One B-rep face of a CAD part: STEP entity #253.
In plain terms, the planar face has unit normal (1, 0, 0).
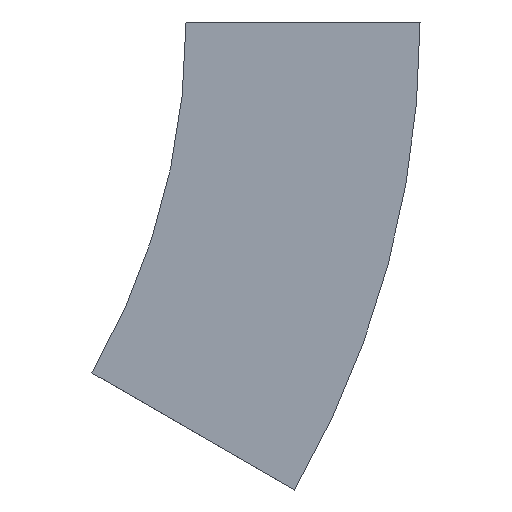
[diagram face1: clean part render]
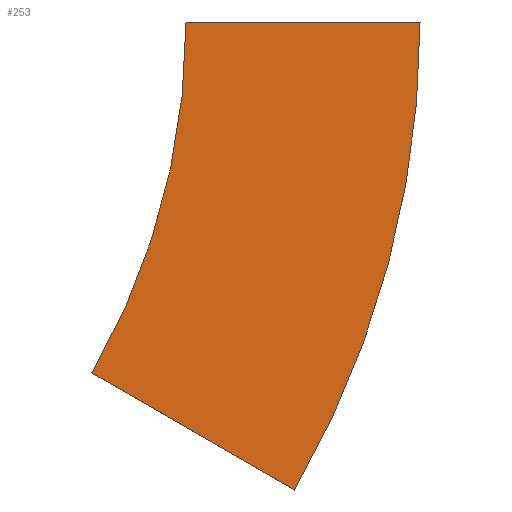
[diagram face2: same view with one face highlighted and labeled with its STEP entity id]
Its self-contained STEP definition (entity closure, numbers rounded to 3 decimals):
#20 = VERTEX_POINT ( 'NONE', #156 ) ;
#25 = VECTOR ( 'NONE', #99, 1000. ) ;
#33 = AXIS2_PLACEMENT_3D ( 'NONE', #85, #275, #437 ) ;
#43 = CIRCLE ( 'NONE', #382, 300. ) ;
#71 = CARTESIAN_POINT ( 'NONE',  ( 0., -46.41, -200. ) ) ;
#72 = ORIENTED_EDGE ( 'NONE', *, *, #209, .F. ) ;
#85 = CARTESIAN_POINT ( 'NONE',  ( 0., -100., 0. ) ) ;
#92 = DIRECTION ( 'NONE',  ( 0., -1., 0. ) ) ;
#99 = DIRECTION ( 'NONE',  ( 0., 1., 0. ) ) ;
#125 = CARTESIAN_POINT ( 'NONE',  ( 0., 0., 0. ) ) ;
#129 = FACE_OUTER_BOUND ( 'NONE', #481, .T. ) ;
#144 = CIRCLE ( 'NONE', #394, 400. ) ;
#146 = VERTEX_POINT ( 'NONE', #125 ) ;
#156 = CARTESIAN_POINT ( 'NONE',  ( 0., 40.192, -150. ) ) ;
#175 = LINE ( 'NONE', #306, #251 ) ;
#180 = CARTESIAN_POINT ( 'NONE',  ( 0., -100., 0. ) ) ;
#209 = EDGE_CURVE ( 'NONE', #483, #146, #294, .T. ) ;
#251 = VECTOR ( 'NONE', #469, 1000. ) ;
#253 = ADVANCED_FACE ( 'NONE', ( #129 ), #473, .F. ) ;
#275 = DIRECTION ( 'NONE',  ( -1., 0., 0. ) ) ;
#278 = CARTESIAN_POINT ( 'NONE',  ( 0., 300., 0. ) ) ;
#281 = ORIENTED_EDGE ( 'NONE', *, *, #511, .T. ) ;
#294 = LINE ( 'NONE', #180, #25 ) ;
#306 = CARTESIAN_POINT ( 'NONE',  ( 0., -46.41, -200. ) ) ;
#316 = CARTESIAN_POINT ( 'NONE',  ( 0., 300., 0. ) ) ;
#328 = VERTEX_POINT ( 'NONE', #71 ) ;
#348 = EDGE_CURVE ( 'NONE', #328, #20, #175, .T. ) ;
#365 = DIRECTION ( 'NONE',  ( 1., 0., 0. ) ) ;
#382 = AXIS2_PLACEMENT_3D ( 'NONE', #278, #365, #477 ) ;
#394 = AXIS2_PLACEMENT_3D ( 'NONE', #316, #519, #92 ) ;
#437 = DIRECTION ( 'NONE',  ( 0., 0., 1. ) ) ;
#443 = EDGE_CURVE ( 'NONE', #146, #20, #43, .T. ) ;
#448 = ORIENTED_EDGE ( 'NONE', *, *, #348, .T. ) ;
#450 = CARTESIAN_POINT ( 'NONE',  ( 0., -100., 0. ) ) ;
#469 = DIRECTION ( 'NONE',  ( 0., 0.866, 0.5 ) ) ;
#473 = PLANE ( 'NONE',  #33 ) ;
#477 = DIRECTION ( 'NONE',  ( 0., -1., 0. ) ) ;
#481 = EDGE_LOOP ( 'NONE', ( #513, #72, #281, #448 ) ) ;
#483 = VERTEX_POINT ( 'NONE', #450 ) ;
#511 = EDGE_CURVE ( 'NONE', #483, #328, #144, .T. ) ;
#513 = ORIENTED_EDGE ( 'NONE', *, *, #443, .F. ) ;
#519 = DIRECTION ( 'NONE',  ( 1., 0., 0. ) ) ;
